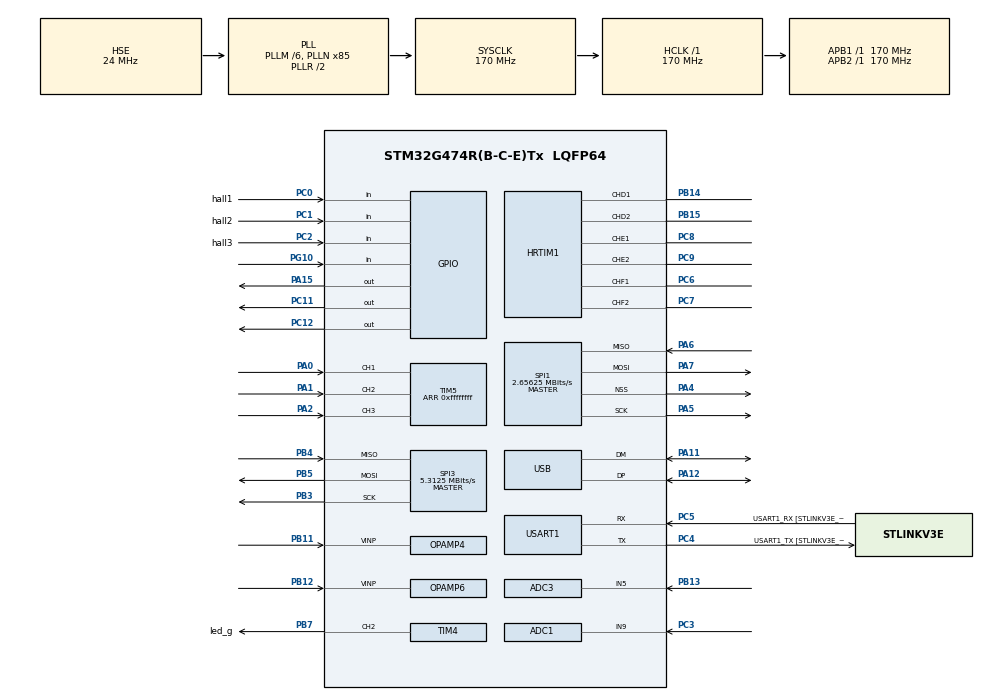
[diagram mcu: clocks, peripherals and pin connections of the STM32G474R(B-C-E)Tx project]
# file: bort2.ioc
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ADC1.Channel-10\#ChannelRegularConversion=ADC_CHANNEL_9
ADC1.ClockPrescaler=ADC_CLOCK_SYNC_PCLK_DIV4
ADC1.EOCSelection=ADC_EOC_SEQ_CONV
ADC1.EnableInjectedConversion=ENABLE
ADC1.EnableRegularConversion=ENABLE
ADC1.ExternalTrigConv=ADC_EXTERNALTRIG_HRTIM_TRG5
ADC1.ExternalTrigInjecConv=ADC_EXTERNALTRIGINJEC_HRTIM_TRG5
ADC1.InjNumberOfConversion=2
ADC1.InjectedChannel-7\#ChannelInjectedConversion=ADC_CHANNEL_11
ADC1.InjectedChannel-9\#ChannelInjectedConversion=ADC_CHANNEL_11
ADC1.InjectedOffsetNumber-7\#ChannelInjectedConversion=ADC_OFFSET_NONE
ADC1.InjectedOffsetNumber-9\#ChannelInjectedConversion=ADC_OFFSET_NONE
ADC1.InjectedRank-7\#ChannelInjectedConversion=1
ADC1.InjectedRank-9\#ChannelInjectedConversion=2
ADC1.InjectedSamplingTime-7\#ChannelInjectedConversion=ADC_SAMPLETIME_12CYCLES_5
ADC1.InjectedSamplingTime-9\#ChannelInjectedConversion=ADC_SAMPLETIME_6CYCLES_5
ADC1.NbrOfConversion=1
ADC1.NbrOfConversionFlag=1
ADC1.OffsetNumber-10\#ChannelRegularConversion=ADC_OFFSET_NONE
ADC1.Overrun=ADC_OVR_DATA_OVERWRITTEN
ADC1.Rank-10\#ChannelRegularConversion=1
ADC1.SamplingTime-10\#ChannelRegularConversion=ADC_SAMPLETIME_92CYCLES_5
ADC1.master=1
ADC2.ClockPrescaler=ADC_CLOCK_SYNC_PCLK_DIV4
ADC2.EnableInjectedConversion=ENABLE
ADC2.EnableRegularConversion=DISABLE
ADC2.ExternalTrigInjecConv=ADC_EXTERNALTRIGINJEC_HRTIM_TRG5
ADC2.InjNumberOfConversion=1
ADC2.InjectedChannel-7\#ChannelInjectedConversion=ADC_CHANNEL_14
ADC2.InjectedOffsetNumber-7\#ChannelInjectedConversion=ADC_OFFSET_NONE
ADC2.InjectedRank-7\#ChannelInjectedConversion=1
ADC2.InjectedSamplingTime-7\#ChannelInjectedConversion=ADC_SAMPLETIME_2CYCLES_5
ADC2.Overrun=ADC_OVR_DATA_OVERWRITTEN
ADC2.Rank1_Channel=ADC_CHANNEL_14
ADC3.ClockPrescaler=ADC_CLOCK_SYNC_PCLK_DIV4
ADC3.EOCSelection=ADC_EOC_SEQ_CONV
ADC3.EnableInjectedConversion=ENABLE
ADC3.EnableInjectedOversampling=DISABLE
ADC3.EnableRegularConversion=DISABLE
ADC3.ExternalTrigInjecConv=ADC_EXTERNALTRIGINJEC_HRTIM_TRG5
ADC3.InjNumberOfConversion=2
ADC3.InjectedChannel-5\#ChannelInjectedConversion=ADC_CHANNEL_VOPAMP3_ADC3
ADC3.InjectedChannel-6\#ChannelInjectedConversion=ADC_CHANNEL_5
ADC3.InjectedOffsetNumber-5\#ChannelInjectedConversion=ADC_OFFSET_NONE
ADC3.InjectedOffsetNumber-6\#ChannelInjectedConversion=ADC_OFFSET_NONE
ADC3.InjectedRank-5\#ChannelInjectedConversion=1
ADC3.InjectedRank-6\#ChannelInjectedConversion=2
ADC3.InjectedSamplingTime-5\#ChannelInjectedConversion=ADC_SAMPLETIME_12CYCLES_5
ADC3.InjectedSamplingTime-6\#ChannelInjectedConversion=ADC_SAMPLETIME_12CYCLES_5
ADC3.Overrun=ADC_OVR_DATA_OVERWRITTEN
ADC3.Rank1_Channel=ADC_CHANNEL_VOPAMP3_ADC3
ADC3.Rank2_Channel=ADC_CHANNEL_5
ADC3.Rank3_Channel=ADC_CHANNEL_5
ADC3.Rank4_Channel=ADC_CHANNEL_VOPAMP3_ADC3
ADC3.master=1
ADC4.ClockPrescaler=ADC_CLOCK_SYNC_PCLK_DIV4
ADC4.EnableInjectedConversion=ENABLE
ADC4.EnableRegularConversion=DISABLE
ADC4.ExternalTrigInjecConv=ADC_EXTERNALTRIGINJEC_HRTIM_TRG5
ADC4.InjNumberOfConversion=1
ADC4.InjectedChannel-3\#ChannelInjectedConversion=ADC_CHANNEL_VOPAMP6
ADC4.InjectedOffsetNumber-3\#ChannelInjectedConversion=ADC_OFFSET_NONE
ADC4.InjectedRank-3\#ChannelInjectedConversion=1
ADC4.InjectedSamplingTime-3\#ChannelInjectedConversion=ADC_SAMPLETIME_12CYCLES_5
ADC4.Overrun=ADC_OVR_DATA_OVERWRITTEN
ADC4.Rank1_Channel=ADC_CHANNEL_VOPAMP6
ADC5.ClockPrescaler=ADC_CLOCK_SYNC_PCLK_DIV4
ADC5.EnableInjectedConversion=ENABLE
ADC5.EnableRegularConversion=DISABLE
ADC5.ExternalTrigInjecConv=ADC_EXTERNALTRIGINJEC_HRTIM_TRG5
ADC5.InjNumberOfConversion=1
ADC5.InjectedChannel-5\#ChannelInjectedConversion=ADC_CHANNEL_VOPAMP4
ADC5.InjectedOffsetNumber-5\#ChannelInjectedConversion=ADC_OFFSET_NONE
ADC5.InjectedRank-5\#ChannelInjectedConversion=1
ADC5.InjectedSamplingTime-5\#ChannelInjectedConversion=ADC_SAMPLETIME_12CYCLES_5
ADC5.Overrun=ADC_OVR_DATA_OVERWRITTEN
ADC5.Rank1_Channel=ADC_CHANNEL_VOPAMP4
Dma.Request0=SPI3_TX
Dma.Request1=SPI3_RX
Dma.SPI3_RX.1.Direction=DMA_PERIPH_TO_MEMORY
Dma.SPI3_RX.1.EventEnable=DISABLE
Dma.SPI3_RX.1.Instance=DMA1_Channel2
Dma.SPI3_RX.1.MemDataAlignment=DMA_MDATAALIGN_HALFWORD
Dma.SPI3_RX.1.MemInc=DMA_MINC_ENABLE
Dma.SPI3_RX.1.Mode=DMA_NORMAL
Dma.SPI3_RX.1.PeriphDataAlignment=DMA_PDATAALIGN_HALFWORD
Dma.SPI3_RX.1.PeriphInc=DMA_PINC_DISABLE
Dma.SPI3_RX.1.Polarity=HAL_DMAMUX_REQ_GEN_RISING
Dma.SPI3_RX.1.Priority=DMA_PRIORITY_LOW
Dma.SPI3_RX.1.RequestNumber=1
Dma.SPI3_RX.1.SignalID=NONE
Dma.SPI3_RX.1.SyncEnable=DISABLE
Dma.SPI3_RX.1.SyncPolarity=HAL_DMAMUX_SYNC_NO_EVENT
Dma.SPI3_RX.1.SyncRequestNumber=1
Dma.SPI3_RX.1.SyncSignalID=NONE
Dma.SPI3_TX.0.Direction=DMA_MEMORY_TO_PERIPH
Dma.SPI3_TX.0.EventEnable=DISABLE
Dma.SPI3_TX.0.Instance=DMA1_Channel1
Dma.SPI3_TX.0.MemDataAlignment=DMA_MDATAALIGN_HALFWORD
Dma.SPI3_TX.0.MemInc=DMA_MINC_ENABLE
Dma.SPI3_TX.0.Mode=DMA_NORMAL
Dma.SPI3_TX.0.PeriphDataAlignment=DMA_PDATAALIGN_HALFWORD
Dma.SPI3_TX.0.PeriphInc=DMA_PINC_DISABLE
Dma.SPI3_TX.0.Polarity=HAL_DMAMUX_REQ_GEN_RISING
Dma.SPI3_TX.0.Priority=DMA_PRIORITY_LOW
Dma.SPI3_TX.0.RequestNumber=1
Dma.SPI3_TX.0.SignalID=NONE
Dma.SPI3_TX.0.SyncEnable=DISABLE
Dma.SPI3_TX.0.SyncPolarity=HAL_DMAMUX_SYNC_NO_EVENT
Dma.SPI3_TX.0.SyncRequestNumber=1
Dma.SPI3_TX.0.SyncSignalID=NONE
HRTIM1.ADCTrigger1_Source1=HRTIM_ADCTRIGGEREVENT13_TIMERF_RESET
HRTIM1.ADCTrigger2_Source1=HRTIM_ADCTRIGGEREVENT24_TIMERF_PERIOD
HRTIM1.ADCTrigger_Id1=HRTIM_ADCTRIGGER_1
HRTIM1.ADCTrigger_Id2=__NULL
HRTIM1.ADCTrigger_Id3=__NULL
HRTIM1.ADCTrigger_Id5=HRTIM_ADCTRIGGER_5
HRTIM1.ADCTrigger_Id6=__NULL
HRTIM1.ADCTrigger_Id7=__NULL
HRTIM1.Adrom_TF=HRTIM_TIM_ADROM_VALLEY
HRTIM1.Configuration_TD=Simple
HRTIM1.Configuration_TE=Simple
HRTIM1.Configuration_TF=Simple
HRTIM1.EnableCalibration=DLLSimpleCalibration
HRTIM1.NumberADCTriggerSource1=1
HRTIM1.NumberADCTriggerSource2=1
HRTIM1.OCChannel_TD1=HRTIM_OUTPUT_TD1
HRTIM1.OCChannel_TE1=HRTIM_OUTPUT_TE1
HRTIM1.OCChannel_TF1=HRTIM_OUTPUT_TF1
HRTIM1.OCChannel_TF2=__NULL
HRTIM1.OCMode_TD1=HRTIM_BASICOCMODE_ACTIVE
HRTIM1.OCMode_TE1=HRTIM_BASICOCMODE_ACTIVE
HRTIM1.OCMode_TF1=HRTIM_BASICOCMODE_ACTIVE
HRTIM1.OCMode_TF2=HRTIM_BASICOCMODE_INACTIVE
HRTIM1.OCPolarity_TD1=HRTIM_OUTPUTPOLARITY_HIGH
HRTIM1.OCPolarity_TE1=HRTIM_OUTPUTPOLARITY_HIGH
HRTIM1.OCPolarity_TF1=HRTIM_OUTPUTPOLARITY_HIGH
HRTIM1.OCPulse_TD1=hrperiod/2
HRTIM1.OCPulse_TE1=hrperiod/2
HRTIM1.OCPulse_TF1=hrperiod/2
HRTIM1.OCPulse_TF2=4000
HRTIM1.ORingUpdateSource_ADCTrigger1=HRTIM_ADCTRIGGERUPDATE_TIMER_F
HRTIM1.ORingUpdateSource_ADCTrigger5=HRTIM_ADCTRIGGERUPDATE_TIMER_F
HRTIM1.PWMChannel_TF1=__NULL
HRTIM1.PWMChannel_TF2=__NULL
HRTIM1.Periode_TD=hrperiod
HRTIM1.Periode_TE=hrperiod
HRTIM1.Periode_TF=hrperiod
HRTIM1.PrescalerRatio_TF=HRTIM_PRESCALERRATIO_MUL32
HRTIM1.Source_ADCTrigger5=HRTIM_ADCTRIGGEREVENT579_TIMERF_PERIOD
HRTIM1.UpDownMode-Output_TD1TD2=HRTIM_TIMERUPDOWNMODE_UPDOWN
HRTIM1.UpDownMode-Output_TE1TE2=HRTIM_TIMERUPDOWNMODE_UPDOWN
HRTIM1.UpDownMode-Output_TF1TF2=HRTIM_TIMERUPDOWNMODE_UPDOWN
HRTIM1.postscaler5=0
Mcu.Family=STM32G4
Mcu.Name=STM32G474R(B-C-E)Tx
Mcu.Package=LQFP64
Mcu.UserConstants=hrperiod,27200*2;main_loop_period,170e6/10000
NVIC.ADC1_2_IRQn=true\:0\:0\:false\:false\:true\:true\:true
NVIC.DMA1_Channel1_IRQn=true\:0\:0\:false\:false\:true\:false\:true
NVIC.DMA1_Channel2_IRQn=true\:0\:0\:false\:false\:true\:false\:true
NVIC.HRTIM1_Master_IRQn=true\:0\:0\:false\:false\:true\:false\:true
NVIC.PriorityGroup=NVIC_PRIORITYGROUP_4
NVIC.TIM1_UP_TIM16_IRQn=true\:0\:0\:false\:false\:true\:true\:true
NVIC.USB_HP_IRQn=true\:0\:0\:false\:false\:true\:true\:true
NVIC.USB_LP_IRQn=true\:0\:0\:false\:false\:true\:true\:true
OPAMP3.PowerMode=OPAMP_POWERMODE_HIGHSPEED
OPAMP4.PowerMode=OPAMP_POWERMODE_HIGHSPEED
OPAMP6.PowerMode=OPAMP_POWERMODE_HIGHSPEED
PA0.Signal=S_TIM5_CH1
PA1.Signal=S_TIM5_CH2
PA11.Mode=Device
PA11.Signal=USB_DM
PA12.Mode=Device
PA12.Signal=USB_DP
PA13.GPIO_Label=T_SWDIO
PA13.Signal=SYS_JTMS-SWDIO
PA14.GPIO_Label=T_SWCLK
PA14.Signal=SYS_JTCK-SWCLK
PA15.GPIO_Speed=GPIO_SPEED_FREQ_VERY_HIGH
PA15.PinState=GPIO_PIN_SET
PA15.Signal=GPIO_Output
PA2.Signal=S_TIM5_CH3
PA4.Mode=NSS_Signal_Hard_Output
PA4.Signal=SPI1_NSS
PA5.Mode=Full_Duplex_Master
PA5.Signal=SPI1_SCK
PA6.Mode=Full_Duplex_Master
PA6.Signal=SPI1_MISO
PA7.Mode=Full_Duplex_Master
PA7.Signal=SPI1_MOSI
PB11.Signal=SharedAnalog_PB11
PB12.Signal=SharedAnalog_PB12
PB13.Signal=SharedAnalog_PB13
PB14.Mode=Output_TD1TD2
PB14.Signal=HRTIM1_CHD1
PB15.Mode=Output_TD1TD2
PB15.Signal=HRTIM1_CHD2
PB3.GPIO_Speed=GPIO_SPEED_FREQ_VERY_HIGH
PB3.Mode=Full_Duplex_Master
PB3.Signal=SPI3_SCK
PB4.GPIO_Speed=GPIO_SPEED_FREQ_VERY_HIGH
PB4.Mode=Full_Duplex_Master
PB4.Signal=SPI3_MISO
PB5.GPIO_Speed=GPIO_SPEED_FREQ_VERY_HIGH
PB5.Mode=Full_Duplex_Master
PB5.Signal=SPI3_MOSI
PB7.GPIO_Label=led_g
PB7.GPIO_Speed=GPIO_SPEED_FREQ_VERY_HIGH
PB7.Signal=S_TIM4_CH2
PC0.GPIO_Label=hall1
PC0.Signal=GPIO_Input
PC1.GPIO_Label=hall2
PC1.Signal=GPIO_Input
PC11.Signal=GPIO_Output
PC12.GPIO_Speed=GPIO_SPEED_FREQ_VERY_HIGH
PC12.PinState=GPIO_PIN_SET
PC12.Signal=GPIO_Output
PC14-OSC32_IN.Mode=LSE-External-Oscillator
PC14-OSC32_IN.Signal=RCC_OSC32_IN
PC15-OSC32_OUT.Mode=LSE-External-Oscillator
PC15-OSC32_OUT.Signal=RCC_OSC32_OUT
PC2.GPIO_Label=hall3
PC2.Signal=GPIO_Input
PC3.Mode=IN9-Single-Ended
PC3.Signal=ADC1_IN9
PC4.GPIO_Label=USART1_TX [STLINKV3E_VCP_RX]
PC4.Mode=Asynchronous
PC4.Signal=USART1_TX
PC5.GPIO_Label=USART1_RX [STLINKV3E_VCP_TX]
PC5.Mode=Asynchronous
PC5.Signal=USART1_RX
PC6.Mode=Output_TF1TF2
PC6.Signal=HRTIM1_CHF1
PC7.Mode=Output_TF1TF2
PC7.Signal=HRTIM1_CHF2
PC8.Mode=Output_TE1TE2
PC8.Signal=HRTIM1_CHE1
PC9.Mode=Output_TE1TE2
PC9.Signal=HRTIM1_CHE2
PF0-OSC_IN.Mode=HSE-External-Oscillator
PF0-OSC_IN.Signal=RCC_OSC_IN
PF1-OSC_OUT.Mode=HSE-External-Oscillator
PF1-OSC_OUT.Signal=RCC_OSC_OUT
PG10-NRST.Signal=GPIO_Input
ProjectManager.HeapSize=0x2000
ProjectManager.StackSize=0x4000
ProjectManager.TargetToolchain=Makefile
RCC.ADC12CLockSelection=RCC_ADC12CLKSOURCE_PLL
RCC.ADC12Freq_Value=56666666.666666664
RCC.ADC345CLockSelection=RCC_ADC345CLKSOURCE_PLL
RCC.ADC345Freq_Value=56666666.666666664
RCC.AHBFreq_Value=170000000
RCC.APB1Freq_Value=170000000
RCC.APB1TimFreq_Value=170000000
RCC.APB2Freq_Value=170000000
RCC.APB2TimFreq_Value=170000000
RCC.CK48CLockSelection=RCC_USBCLKSOURCE_HSI48
RCC.CortexFreq_Value=170000000
RCC.EXTERNAL_CLOCK_VALUE=12288000
RCC.HCLKFreq_Value=170000000
RCC.HSE_VALUE=24000000
RCC.HSI48_VALUE=48000000
RCC.HSI_VALUE=16000000
RCC.PLLM=RCC_PLLM_DIV6
RCC.PLLN=85
RCC.PLLP=RCC_PLLP_DIV6
RCC.PLLQ=RCC_PLLQ_DIV8
RCC.PLLSourceVirtual=RCC_PLLSOURCE_HSE
RCC.PREFETCH_ENABLE=1
RCC.RTCClockSelection=RCC_RTCCLKSOURCE_LSE
RCC.SYSCLKFreq_VALUE=170000000
RCC.SYSCLKSource=RCC_SYSCLKSOURCE_PLLCLK
RCC.USBFreq_Value=48000000
RCC.VCOOutputFreq_Value=340000000
SH.S_TIM4_CH2.0=TIM4_CH2,PWM Generation2 CH2
SH.S_TIM5_CH1.0=TIM5_CH1,Encoder_Interface
SH.S_TIM5_CH2.0=TIM5_CH2,Encoder_Interface
SH.S_TIM5_CH3.0=TIM5_CH3,Input_Capture3_from_TI3
SH.SharedAnalog_PB11.0=OPAMP4_VINP,Follower_Internally_Connected
SH.SharedAnalog_PB11.1=ADC2_IN14,IN14-Single-Ended
SH.SharedAnalog_PB12.0=OPAMP6_VINP,Follower_Internally_Connected
SH.SharedAnalog_PB12.1=ADC1_IN11,IN11-Single-Ended
SH.SharedAnalog_PB13.0=ADC3_IN5,IN5-Single-Ended
SH.SharedAnalog_PB13.1=OPAMP3_VINP,Follower_Internally_Connected
SPI1.BaudRatePrescaler=SPI_BAUDRATEPRESCALER_64
SPI1.CalculateBaudRate=2.65625 MBits/s
SPI1.DataSize=SPI_DATASIZE_16BIT
SPI1.Direction=SPI_DIRECTION_2LINES
SPI1.Mode=SPI_MODE_MASTER
SPI1.TIMode=SPI_TIMODE_ENABLE
SPI1.VirtualNSS=VM_NSSHARD
SPI1.VirtualType=VM_MASTER
SPI3.BaudRatePrescaler=SPI_BAUDRATEPRESCALER_32
SPI3.CLKPhase=SPI_PHASE_2EDGE
SPI3.CLKPolarity=SPI_POLARITY_LOW
SPI3.CalculateBaudRate=5.3125 MBits/s
SPI3.DataSize=SPI_DATASIZE_16BIT
SPI3.Direction=SPI_DIRECTION_2LINES
SPI3.Mode=SPI_MODE_MASTER
SPI3.VirtualType=VM_MASTER
TIM1.PeriodNoDither=main_loop_period-1
TIM4.Channel-PWM\ Generation2\ CH2=TIM_CHANNEL_2
TIM4.PeriodNoDither=0xFFFF
TIM5.Channel-Input_Capture3_from_TI3=TIM_CHANNEL_3
TIM5.EncoderMode=TIM_ENCODERMODE_TI12
TIM5.IC1Filter=1
TIM5.IC2Filter=1
TIM5.ICFilter_CH3=2
TIM5.PeriodNoDither=0xffffffff
USART1.VirtualMode-Asynchronous=VM_ASYNC
USART1.WordLength=WORDLENGTH_8B
VP_ADC3_OPAMP_INTERNAL3.Mode=IN-OPAMP3
VP_ADC4_OPAMP_INTERNAL6.Mode=IN-OPAMP6
VP_ADC5_OPAMP_INTERNAL4.Mode=IN-OPAMP4
VP_RCC_VS_USB.Mode=USB_FS
VP_SYS_VS_DBSignals.Mode=DisableDeadBatterySignals
VP_TIM1_VS_ClockSourceINT.Mode=Internal
board=NUCLEO-G474RE

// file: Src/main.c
/* USER CODE BEGIN Header */
/**
  ******************************************************************************
  * @file           : main.c
  * @brief          : Main program body
  ******************************************************************************
  * @attention
  *
  * <h2><center>&copy; Copyright (c) 2019 STMicroelectronics.
  * All rights reserved.</center></h2>
  *
  * This software component is licensed by ST under Ultimate Liberty license
  * SLA0044, the "License"; You may not use this file except in compliance with
  * the License. You may obtain a copy of the License at:
  *                             www.st.com/SLA0044
  *
  ******************************************************************************
  */
/* USER CODE END Header */

#include "main.h"

/* USER CODE BEGIN Includes */
#include "../motorlib/system.h"
uint8_t go_to_bootloader = 0;
/* USER CODE END Includes */

ADC_HandleTypeDef hadc1;
ADC_HandleTypeDef hadc2;
ADC_HandleTypeDef hadc3;
ADC_HandleTypeDef hadc4;
ADC_HandleTypeDef hadc5;

HRTIM_HandleTypeDef hhrtim1;

OPAMP_HandleTypeDef hopamp3;
OPAMP_HandleTypeDef hopamp4;
OPAMP_HandleTypeDef hopamp6;

SPI_HandleTypeDef hspi1;
SPI_HandleTypeDef hspi3;
DMA_HandleTypeDef hdma_spi3_tx;
DMA_HandleTypeDef hdma_spi3_rx;

TIM_HandleTypeDef htim1;
TIM_HandleTypeDef htim4;
TIM_HandleTypeDef htim5;

UART_HandleTypeDef huart1;

PCD_HandleTypeDef hpcd_USB_FS;

/* USER CODE BEGIN PV */
#include "../motorlib/param.h"
//#include "main2.h"

/* USER CODE END PV */

void SystemClock_Config(void);
static void MX_GPIO_Init(void);
static void MX_USART1_UART_Init(void);
static void MX_HRTIM1_Init(void);
static void MX_ADC1_Init(void);
static void MX_ADC2_Init(void);
static void MX_ADC3_Init(void);
static void MX_TIM5_Init(void);
static void MX_SPI1_Init(void);
static void MX_SPI3_Init(void);
static void MX_DMA_Init(void);
static void MX_ADC4_Init(void);
static void MX_ADC5_Init(void);
static void MX_OPAMP3_Init(void);
static void MX_OPAMP4_Init(void);
static void MX_OPAMP6_Init(void);
static void MX_USB_PCD_Init(void);
static void MX_TIM1_Init(void);
static void MX_TIM4_Init(void);

/* USER CODE BEGIN 0 */
uint16_t drv_regs_error = 0;

uint16_t drv_regs[] = {
  (2<<11) | 0x00,  // control_reg 0x00, 6 PWM mode
  (3<<11) | 0x3AA, // hs_reg      0x3CC, moderate drive current
  (4<<11) | 0x2FF, // ls_reg      0x0CC, no cycle by cycle, 500 ns tdrive
                                // moderate drive current (.57,1.14A)
  (5<<11) | 0x020,  // ocp_reg     0x20 -> 50 ns dead time,
                              //latched ocp, 4 us ocp deglitch, 0.06 Vds thresh
  //(6<<11) | 0x2C0, // csa_reg     0x2C0 -> bidirectional current, 40V/V
  (6<<11) | 0x280, // csa_reg     0x280 -> bidirectional current, 20V/V
};

/* USER CODE END 0 */

int main(void)
{
  /* USER CODE BEGIN 1 */
  // DWC CYCCNT used as main counter
  CoreDebug->DEMCR |= CoreDebug_DEMCR_TRCENA_Msk;
  DWT->CYCCNT = 0;
  DWT->CTRL |= DWT_CTRL_CYCCNTENA_Msk;
  /* USER CODE END 1 */

  /* MCU Configuration--------------------------------------------------------*/

  /* Reset of all peripherals, Initializes the Flash interface and the Systick. */
  HAL_Init();

  /* USER CODE BEGIN Init */
  RCC->APB1ENR1 |= RCC_APB1ENR1_CRSEN;      // Clock recovery circuit, enables syncing HSI48 MHz to USB clock
  /* USER CODE END Init */

  /* Configure the system clock */
  SystemClock_Config();

  /* USER CODE BEGIN SysInit */
  DWT->CTRL = 0x400003FF | (1ul<<17) | DWT_CTRL_LSUEVTENA_Msk | DWT_CTRL_FOLDEVTENA_Msk;
  system_init();
  /* USER CODE END SysInit */

  /* Initialize all configured peripherals */
  MX_GPIO_Init();
  MX_USART1_UART_Init();
  MX_HRTIM1_Init();
  MX_ADC1_Init();
  MX_ADC2_Init();
  MX_ADC3_Init();
  MX_TIM5_Init();
  MX_SPI1_Init();
  MX_SPI3_Init();
  MX_DMA_Init();
  MX_ADC4_Init();
  MX_ADC5_Init();
  MX_OPAMP3_Init();
  MX_OPAMP4_Init();
  MX_OPAMP6_Init();
  MX_USB_PCD_Init();
  MX_TIM1_Init();
  MX_TIM4_Init();
  /* USER CODE BEGIN 2 */

  HAL_ADC_Start(&hadc1);
  HAL_ADC_Start(&hadc2);
  HAL_ADC_Start(&hadc3);
  HAL_ADC_Start(&hadc4);
  HAL_ADC_Start(&hadc5);

  HAL_OPAMP_Start(&hopamp3);
  HAL_OPAMP_Start(&hopamp4);
  OPAMP6->CSR |= OPAMP_CSR_OPAMPINTEN; // bug in cubemx
  HAL_OPAMP_Start(&hopamp6);
  HAL_Delay(100);

    SPI3->CR1 |= SPI_CR1_SPE;

  GPIOC->ODR |= GPIO_ODR_OD11; // drv enable
  HAL_Delay(10);

  for (uint8_t i=0; i<sizeof(drv_regs)/sizeof(uint16_t); i++) {
    uint16_t reg_out = drv_regs[i];
    uint16_t reg_in = 0;
    HAL_SPI_TransmitReceive(&hspi1, (uint8_t *) &reg_out, (uint8_t *) &reg_in, 1, 10);
     reg_out |= (1<<15); // switch to read mode
     HAL_SPI_TransmitReceive(&hspi1, (uint8_t *) &reg_out, (uint8_t *) &reg_in, 1, 10);
    if ((reg_in & 0x7FF) != (reg_out & 0x7FF)) {
      drv_regs_error |= 1 << i;
    }
  }
  uint32_t deadtime = 10;
  uint32_t deadprescale = 0;
  HRTIM1->sTimerxRegs[3].OUTxR |= HRTIM_OUTR_DTEN;
  HRTIM1->sTimerxRegs[3].DTxR |= (deadtime << HRTIM_DTR_DTF_Pos) | (deadtime << HRTIM_DTR_DTR_Pos) | (deadprescale << HRTIM_DTR_DTPRSC_Pos);
  HRTIM1->sTimerxRegs[3].TIMxCR |= HRTIM_TIMCR_PREEN | HRTIM_TIMCR_TRSTU;
  HRTIM1->sTimerxRegs[4].OUTxR |= HRTIM_OUTR_DTEN;
  HRTIM1->sTimerxRegs[4].DTxR |= (deadtime << HRTIM_DTR_DTF_Pos) | (deadtime << HRTIM_DTR_DTR_Pos) | (deadprescale << HRTIM_DTR_DTPRSC_Pos);
  HRTIM1->sTimerxRegs[4].TIMxCR |= HRTIM_TIMCR_PREEN | HRTIM_TIMCR_TRSTU;
  HRTIM1->sTimerxRegs[5].OUTxR |= HRTIM_OUTR_DTEN;
  HRTIM1->sTimerxRegs[5].DTxR |= (deadtime << HRTIM_DTR_DTF_Pos) | (deadtime << HRTIM_DTR_DTR_Pos) | (deadprescale << HRTIM_DTR_DTPRSC_Pos);
  HRTIM1->sTimerxRegs[5].TIMxCR |= HRTIM_TIMCR_PREEN | HRTIM_TIMCR_TRSTU;

  //HRTIM1->sCommonRegs.CR2 |= HRTIM_CR2_TESWU;
  HRTIM1->sMasterRegs.MCR |= HRTIM_MCR_TDCEN + HRTIM_MCR_TECEN + HRTIM_MCR_TFCEN;

  HAL_HRTIM_SimplePWMStart(&hhrtim1, HRTIM_TIMERINDEX_TIMER_D, HRTIM_OUTPUT_TD1);
  HAL_HRTIM_SimplePWMStart(&hhrtim1, HRTIM_TIMERINDEX_TIMER_D, HRTIM_OUTPUT_TD2);
  HAL_HRTIM_SimplePWMStart(&hhrtim1, HRTIM_TIMERINDEX_TIMER_E, HRTIM_OUTPUT_TE2);
  HAL_HRTIM_SimplePWMStart(&hhrtim1, HRTIM_TIMERINDEX_TIMER_E, HRTIM_OUTPUT_TF1);
  HAL_HRTIM_SimplePWMStart(&hhrtim1, HRTIM_TIMERINDEX_TIMER_F, HRTIM_OUTPUT_TE1);
  HAL_HRTIM_SimplePWMStart(&hhrtim1, HRTIM_TIMERINDEX_TIMER_F, HRTIM_OUTPUT_TF2);
  hadc1.Instance->CR |= ADC_CR_JADSTART;
  hadc1.Instance->IER |= ADC_IER_JEOCIE;
  hadc2.Instance->CR |= ADC_CR_JADSTART;
  hadc3.Instance->CR |= ADC_CR_JADSTART;
  hadc4.Instance->CR |= ADC_CR_JADSTART;
  hadc5.Instance->CR |= ADC_CR_JADSTART;

  // interrupt priorities
  HAL_NVIC_SetPriority(SysTick_IRQn, 4, 0);
  HAL_NVIC_SetPriority(USB_HP_IRQn, 2, 0);
  HAL_NVIC_SetPriority(USB_LP_IRQn, 3, 0);
  HAL_NVIC_SetPriority(TIM1_UP_TIM16_IRQn, 1, 0);

  HAL_TIM_Encoder_Start(&htim5, TIM_CHANNEL_ALL);
  USB->CNTR &= ~(USB_CNTR_SOFM | USB_CNTR_ESOFM); // Don't need these interrupts
  USB_DevConnect(USB);
  htim1.Instance->DIER |= TIM_DIER_UIE;
  HAL_TIM_Base_Start(&htim1);
  HAL_TIM_Base_Start(&htim4);
  HAL_TIM_IC_Start(&htim5, TIM_CHANNEL_3); // encoder index
  HAL_TIM_OC_Start(&htim4, TIM_CHANNEL_2);

  /* USER CODE END 2 */

  /* Infinite loop */
  /* USER CODE BEGIN WHILE */
  int i = 0;
  while (1)
  {
    i++;
    system_run();
   // USB_send(&i,sizeof(int));
    /* USER CODE END WHILE */

  }
}

void SystemClock_Config(void)
{
  RCC_OscInitTypeDef RCC_OscInitStruct = {0};
  RCC_ClkInitTypeDef RCC_ClkInitStruct = {0};
  RCC_PeriphCLKInitTypeDef PeriphClkInit = {0};
  RCC_CRSInitTypeDef pInit = {0};

  /** Configure the main internal regulator output voltage
  */
  HAL_PWREx_ControlVoltageScaling(PWR_REGULATOR_VOLTAGE_SCALE1_BOOST);
  /** Initializes the CPU, AHB and APB busses clocks
  */
  RCC_OscInitStruct.OscillatorType = RCC_OSCILLATORTYPE_HSI48|RCC_OSCILLATORTYPE_HSE;
  RCC_OscInitStruct.HSEState = RCC_HSE_ON;
  RCC_OscInitStruct.HSI48State = RCC_HSI48_ON;
  RCC_OscInitStruct.PLL.PLLState = RCC_PLL_ON;
  RCC_OscInitStruct.PLL.PLLSource = RCC_PLLSOURCE_HSE;
  RCC_OscInitStruct.PLL.PLLM = RCC_PLLM_DIV6;
  RCC_OscInitStruct.PLL.PLLN = 85;
  RCC_OscInitStruct.PLL.PLLP = RCC_PLLP_DIV6;
  RCC_OscInitStruct.PLL.PLLQ = RCC_PLLQ_DIV8;
  RCC_OscInitStruct.PLL.PLLR = RCC_PLLR_DIV2;
  if (HAL_RCC_OscConfig(&RCC_OscInitStruct) != HAL_OK)
  {
    Error_Handler();
  }
  /** Initializes the CPU, AHB and APB busses clocks
  */
  RCC_ClkInitStruct.ClockType = RCC_CLOCKTYPE_HCLK|RCC_CLOCKTYPE_SYSCLK
                              |RCC_CLOCKTYPE_PCLK1|RCC_CLOCKTYPE_PCLK2;
  RCC_ClkInitStruct.SYSCLKSource = RCC_SYSCLKSOURCE_PLLCLK;
  RCC_ClkInitStruct.AHBCLKDivider = RCC_SYSCLK_DIV1;
  RCC_ClkInitStruct.APB1CLKDivider = RCC_HCLK_DIV1;
  RCC_ClkInitStruct.APB2CLKDivider = RCC_HCLK_DIV1;

  if (HAL_RCC_ClockConfig(&RCC_ClkInitStruct, FLASH_LATENCY_8) != HAL_OK)
  {
    Error_Handler();
  }
  /** Initializes the peripherals clocks
  */
  PeriphClkInit.PeriphClockSelection = RCC_PERIPHCLK_USART1|RCC_PERIPHCLK_USB
                              |RCC_PERIPHCLK_ADC12|RCC_PERIPHCLK_ADC345;
  PeriphClkInit.Usart1ClockSelection = RCC_USART1CLKSOURCE_PCLK2;
  PeriphClkInit.UsbClockSelection = RCC_USBCLKSOURCE_HSI48;
  PeriphClkInit.Adc12ClockSelection = RCC_ADC12CLKSOURCE_PLL;
  PeriphClkInit.Adc345ClockSelection = RCC_ADC345CLKSOURCE_PLL;
  if (HAL_RCCEx_PeriphCLKConfig(&PeriphClkInit) != HAL_OK)
  {
    Error_Handler();
  }
  /** Configures CRS
  */
  pInit.Prescaler = RCC_CRS_SYNC_DIV1;
  pInit.Source = RCC_CRS_SYNC_SOURCE_USB;
  pInit.Polarity = RCC_CRS_SYNC_POLARITY_RISING;
  pInit.ReloadValue = __HAL_RCC_CRS_RELOADVALUE_CALCULATE(48000000,1000);
  pInit.ErrorLimitValue = 34;
  pInit.HSI48CalibrationValue = 32;

  HAL_RCCEx_CRSConfig(&pInit);
}

static void MX_ADC1_Init(void)
{

  ADC_MultiModeTypeDef multimode = {0};
  ADC_InjectionConfTypeDef sConfigInjected = {0};
  ADC_ChannelConfTypeDef sConfig = {0};

  /** Common config
  */
  hadc1.Instance = ADC1;
  hadc1.Init.ClockPrescaler = ADC_CLOCK_SYNC_PCLK_DIV4;
  hadc1.Init.Resolution = ADC_RESOLUTION_12B;
  hadc1.Init.DataAlign = ADC_DATAALIGN_RIGHT;
  hadc1.Init.GainCompensation = 0;
  hadc1.Init.ScanConvMode = ADC_SCAN_ENABLE;
  hadc1.Init.EOCSelection = ADC_EOC_SEQ_CONV;
  hadc1.Init.LowPowerAutoWait = DISABLE;
  hadc1.Init.ContinuousConvMode = DISABLE;
  hadc1.Init.NbrOfConversion = 1;
  hadc1.Init.DiscontinuousConvMode = DISABLE;
  hadc1.Init.ExternalTrigConv = ADC_EXTERNALTRIG_HRTIM_TRG5;
  hadc1.Init.ExternalTrigConvEdge = ADC_EXTERNALTRIGCONVEDGE_RISING;
  hadc1.Init.DMAContinuousRequests = DISABLE;
  hadc1.Init.Overrun = ADC_OVR_DATA_OVERWRITTEN;
  hadc1.Init.OversamplingMode = DISABLE;
  if (HAL_ADC_Init(&hadc1) != HAL_OK)
  {
    Error_Handler();
  }
  /** Configure the ADC multi-mode
  */
  multimode.Mode = ADC_MODE_INDEPENDENT;
  if (HAL_ADCEx_MultiModeConfigChannel(&hadc1, &multimode) != HAL_OK)
  {
    Error_Handler();
  }
  /** Configure Injected Channel
  */
  sConfigInjected.InjectedChannel = ADC_CHANNEL_11;
  sConfigInjected.InjectedRank = ADC_INJECTED_RANK_1;
  sConfigInjected.InjectedSamplingTime = ADC_SAMPLETIME_12CYCLES_5;
  sConfigInjected.InjectedSingleDiff = ADC_SINGLE_ENDED;
  sConfigInjected.InjectedOffsetNumber = ADC_OFFSET_NONE;
  sConfigInjected.InjectedOffset = 0;
  sConfigInjected.InjectedNbrOfConversion = 2;
  sConfigInjected.InjectedDiscontinuousConvMode = DISABLE;
  sConfigInjected.AutoInjectedConv = DISABLE;
  sConfigInjected.QueueInjectedContext = DISABLE;
  sConfigInjected.ExternalTrigInjecConv = ADC_EXTERNALTRIGINJEC_HRTIM_TRG5;
  sConfigInjected.ExternalTrigInjecConvEdge = ADC_EXTERNALTRIGINJECCONV_EDGE_RISING;
  sConfigInjected.InjecOversamplingMode = DISABLE;
  if (HAL_ADCEx_InjectedConfigChannel(&hadc1, &sConfigInjected) != HAL_OK)
  {
    Error_Handler();
  }
  /** Configure Injected Channel
  */
  sConfigInjected.InjectedRank = ADC_INJECTED_RANK_2;
  sConfigInjected.InjectedSamplingTime = ADC_SAMPLETIME_6CYCLES_5;
  if (HAL_ADCEx_InjectedConfigChannel(&hadc1, &sConfigInjected) != HAL_OK)
  {
    Error_Handler();
  }
  /** Configure Regular Channel
  */
  sConfig.Channel = ADC_CHANNEL_9;
  sConfig.Rank = ADC_REGULAR_RANK_1;
  sConfig.SamplingTime = ADC_SAMPLETIME_92CYCLES_5;
  sConfig.SingleDiff = ADC_SINGLE_ENDED;
  sConfig.OffsetNumber = ADC_OFFSET_NONE;
  sConfig.Offset = 0;
  if (HAL_ADC_ConfigChannel(&hadc1, &sConfig) != HAL_OK)
  {
    Error_Handler();
  }

}

static void MX_ADC2_Init(void)
{

  ADC_InjectionConfTypeDef sConfigInjected = {0};

  /** Common config
  */
  hadc2.Instance = ADC2;
  hadc2.Init.ClockPrescaler = ADC_CLOCK_SYNC_PCLK_DIV4;
  hadc2.Init.Resolution = ADC_RESOLUTION_12B;
  hadc2.Init.DataAlign = ADC_DATAALIGN_RIGHT;
  hadc2.Init.GainCompensation = 0;
  hadc2.Init.ScanConvMode = ADC_SCAN_DISABLE;
  hadc2.Init.EOCSelection = ADC_EOC_SINGLE_CONV;
  hadc2.Init.LowPowerAutoWait = DISABLE;
  hadc2.Init.ContinuousConvMode = DISABLE;
  hadc2.Init.NbrOfConversion = 1;
  hadc2.Init.DiscontinuousConvMode = DISABLE;
  hadc2.Init.DMAContinuousRequests = DISABLE;
  hadc2.Init.Overrun = ADC_OVR_DATA_OVERWRITTEN;
  hadc2.Init.OversamplingMode = DISABLE;
  if (HAL_ADC_Init(&hadc2) != HAL_OK)
  {
    Error_Handler();
  }
  /** Configure Injected Channel
  */
  sConfigInjected.InjectedChannel = ADC_CHANNEL_14;
  sConfigInjected.InjectedRank = ADC_INJECTED_RANK_1;
  sConfigInjected.InjectedSamplingTime = ADC_SAMPLETIME_2CYCLES_5;
  sConfigInjected.InjectedSingleDiff = ADC_SINGLE_ENDED;
  sConfigInjected.InjectedOffsetNumber = ADC_OFFSET_NONE;
  sConfigInjected.InjectedOffset = 0;
  sConfigInjected.InjectedNbrOfConversion = 1;
  sConfigInjected.InjectedDiscontinuousConvMode = DISABLE;
  sConfigInjected.AutoInjectedConv = DISABLE;
  sConfigInjected.QueueInjectedContext = DISABLE;
  sConfigInjected.ExternalTrigInjecConv = ADC_EXTERNALTRIGINJEC_HRTIM_TRG5;
  sConfigInjected.ExternalTrigInjecConvEdge = ADC_EXTERNALTRIGINJECCONV_EDGE_RISING;
  sConfigInjected.InjecOversamplingMode = DISABLE;
  if (HAL_ADCEx_InjectedConfigChannel(&hadc2, &sConfigInjected) != HAL_OK)
  {
    Error_Handler();
  }

}

static void MX_ADC3_Init(void)
{

  ADC_MultiModeTypeDef multimode = {0};
  ADC_InjectionConfTypeDef sConfigInjected = {0};

  /** Common config
  */
  hadc3.Instance = ADC3;
  hadc3.Init.ClockPrescaler = ADC_CLOCK_SYNC_PCLK_DIV4;
  hadc3.Init.Resolution = ADC_RESOLUTION_12B;
  hadc3.Init.DataAlign = ADC_DATAALIGN_RIGHT;
  hadc3.Init.GainCompensation = 0;
  hadc3.Init.ScanConvMode = ADC_SCAN_ENABLE;
  hadc3.Init.EOCSelection = ADC_EOC_SEQ_CONV;
  hadc3.Init.LowPowerAutoWait = DISABLE;
  hadc3.Init.ContinuousConvMode = DISABLE;
  hadc3.Init.NbrOfConversion = 1;
  hadc3.Init.DiscontinuousConvMode = DISABLE;
  hadc3.Init.DMAContinuousRequests = DISABLE;
  hadc3.Init.Overrun = ADC_OVR_DATA_OVERWRITTEN;
  hadc3.Init.OversamplingMode = DISABLE;
  if (HAL_ADC_Init(&hadc3) != HAL_OK)
  {
    Error_Handler();
  }
  /** Configure the ADC multi-mode
  */
  multimode.Mode = ADC_MODE_INDEPENDENT;
  if (HAL_ADCEx_MultiModeConfigChannel(&hadc3, &multimode) != HAL_OK)
  {
    Error_Handler();
  }
  /** Configure Injected Channel
  */
  sConfigInjected.InjectedChannel = ADC_CHANNEL_VOPAMP3_ADC3;
  sConfigInjected.InjectedRank = ADC_INJECTED_RANK_1;
  sConfigInjected.InjectedSamplingTime = ADC_SAMPLETIME_12CYCLES_5;
  sConfigInjected.InjectedSingleDiff = ADC_SINGLE_ENDED;
  sConfigInjected.InjectedOffsetNumber = ADC_OFFSET_NONE;
  sConfigInjected.InjectedOffset = 0;
  sConfigInjected.InjectedNbrOfConversion = 2;
  sConfigInjected.InjectedDiscontinuousConvMode = DISABLE;
  sConfigInjected.AutoInjectedConv = DISABLE;
  sConfigInjected.QueueInjectedContext = DISABLE;
  sConfigInjected.ExternalTrigInjecConv = ADC_EXTERNALTRIGINJEC_HRTIM_TRG5;
  sConfigInjected.ExternalTrigInjecConvEdge = ADC_EXTERNALTRIGINJECCONV_EDGE_RISING;
  sConfigInjected.InjecOversamplingMode = DISABLE;
  if (HAL_ADCEx_InjectedConfigChannel(&hadc3, &sConfigInjected) != HAL_OK)
  {
    Error_Handler();
  }
  /** Configure Injected Channel
  */
  sConfigInjected.InjectedChannel = ADC_CHANNEL_5;
  sConfigInjected.InjectedRank = ADC_INJECTED_RANK_2;
  if (HAL_ADCEx_InjectedConfigChannel(&hadc3, &sConfigInjected) != HAL_OK)
  {
    Error_Handler();
  }

}

static void MX_ADC4_Init(void)
{

  ADC_InjectionConfTypeDef sConfigInjected = {0};

  /** Common config
  */
  hadc4.Instance = ADC4;
  hadc4.Init.ClockPrescaler = ADC_CLOCK_SYNC_PCLK_DIV4;
  hadc4.Init.Resolution = ADC_RESOLUTION_12B;
  hadc4.Init.DataAlign = ADC_DATAALIGN_RIGHT;
  hadc4.Init.GainCompensation = 0;
  hadc4.Init.ScanConvMode = ADC_SCAN_DISABLE;
  hadc4.Init.EOCSelection = ADC_EOC_SINGLE_CONV;
  hadc4.Init.LowPowerAutoWait = DISABLE;
  hadc4.Init.ContinuousConvMode = DISABLE;
  hadc4.Init.NbrOfConversion = 1;
  hadc4.Init.DiscontinuousConvMode = DISABLE;
  hadc4.Init.DMAContinuousRequests = DISABLE;
  hadc4.Init.Overrun = ADC_OVR_DATA_OVERWRITTEN;
  hadc4.Init.OversamplingMode = DISABLE;
  if (HAL_ADC_Init(&hadc4) != HAL_OK)
  {
    Error_Handler();
  }
  /** Configure Injected Channel
  */
  sConfigInjected.InjectedChannel = ADC_CHANNEL_VOPAMP6;
  sConfigInjected.InjectedRank = ADC_INJECTED_RANK_1;
  sConfigInjected.InjectedSamplingTime = ADC_SAMPLETIME_12CYCLES_5;
  sConfigInjected.InjectedSingleDiff = ADC_SINGLE_ENDED;
  sConfigInjected.InjectedOffsetNumber = ADC_OFFSET_NONE;
  sConfigInjected.InjectedOffset = 0;
  sConfigInjected.InjectedNbrOfConversion = 1;
  sConfigInjected.InjectedDiscontinuousConvMode = DISABLE;
  sConfigInjected.AutoInjectedConv = DISABLE;
  sConfigInjected.QueueInjectedContext = DISABLE;
  sConfigInjected.ExternalTrigInjecConv = ADC_EXTERNALTRIGINJEC_HRTIM_TRG5;
  sConfigInjected.ExternalTrigInjecConvEdge = ADC_EXTERNALTRIGINJECCONV_EDGE_RISING;
  sConfigInjected.InjecOversamplingMode = DISABLE;
  if (HAL_ADCEx_InjectedConfigChannel(&hadc4, &sConfigInjected) != HAL_OK)
  {
    Error_Handler();
  }

}

static void MX_ADC5_Init(void)
{

  ADC_InjectionConfTypeDef sConfigInjected = {0};

  /** Common config
  */
  hadc5.Instance = ADC5;
  hadc5.Init.ClockPrescaler = ADC_CLOCK_SYNC_PCLK_DIV4;
  hadc5.Init.Resolution = ADC_RESOLUTION_12B;
  hadc5.Init.DataAlign = ADC_DATAALIGN_RIGHT;
  hadc5.Init.GainCompensation = 0;
  hadc5.Init.ScanConvMode = ADC_SCAN_DISABLE;
  hadc5.Init.EOCSelection = ADC_EOC_SINGLE_CONV;
  hadc5.Init.LowPowerAutoWait = DISABLE;
  hadc5.Init.ContinuousConvMode = DISABLE;
  hadc5.Init.NbrOfConversion = 1;
  hadc5.Init.DiscontinuousConvMode = DISABLE;
  hadc5.Init.DMAContinuousRequests = DISABLE;
  hadc5.Init.Overrun = ADC_OVR_DATA_OVERWRITTEN;
  hadc5.Init.OversamplingMode = DISABLE;
  if (HAL_ADC_Init(&hadc5) != HAL_OK)
  {
    Error_Handler();
  }
  /** Configure Injected Channel
  */
  sConfigInjected.InjectedChannel = ADC_CHANNEL_VOPAMP4;
  sConfigInjected.InjectedRank = ADC_INJECTED_RANK_1;
  sConfigInjected.InjectedSamplingTime = ADC_SAMPLETIME_12CYCLES_5;
  sConfigInjected.InjectedSingleDiff = ADC_SINGLE_ENDED;
  sConfigInjected.InjectedOffsetNumber = ADC_OFFSET_NONE;
  sConfigInjected.InjectedOffset = 0;
  sConfigInjected.InjectedNbrOfConversion = 1;
  sConfigInjected.InjectedDiscontinuousConvMode = DISABLE;
  sConfigInjected.AutoInjectedConv = DISABLE;
  sConfigInjected.QueueInjectedContext = DISABLE;
  sConfigInjected.ExternalTrigInjecConv = ADC_EXTERNALTRIGINJEC_HRTIM_TRG5;
  sConfigInjected.ExternalTrigInjecConvEdge = ADC_EXTERNALTRIGINJECCONV_EDGE_RISING;
  sConfigInjected.InjecOversamplingMode = DISABLE;
  if (HAL_ADCEx_InjectedConfigChannel(&hadc5, &sConfigInjected) != HAL_OK)
  {
    Error_Handler();
  }

}

static void MX_HRTIM1_Init(void)
{

  HRTIM_ADCTriggerCfgTypeDef pADCTriggerCfg = {0};
  HRTIM_TimeBaseCfgTypeDef pTimeBaseCfg = {0};
  HRTIM_TimerCtlTypeDef pTimerCtl = {0};
  HRTIM_SimpleOCChannelCfgTypeDef pSimpleOCChannelCfg = {0};

  hhrtim1.Instance = HRTIM1;
  hhrtim1.Init.HRTIMInterruptResquests = HRTIM_IT_NONE;
  hhrtim1.Init.SyncOptions = HRTIM_SYNCOPTION_NONE;
  if (HAL_HRTIM_Init(&hhrtim1) != HAL_OK)
  {
    Error_Handler();
  }
  if (HAL_HRTIM_DLLCalibrationStart(&hhrtim1, HRTIM_CALIBRATIONRATE_3) != HAL_OK)
  {
    Error_Handler();
  }
  if (HAL_HRTIM_PollForDLLCalibration(&hhrtim1, 10) != HAL_OK)
  {
    Error_Handler();
  }
  pADCTriggerCfg.UpdateSource = HRTIM_ADCTRIGGERUPDATE_TIMER_F;
  pADCTriggerCfg.Trigger = HRTIM_ADCTRIGGEREVENT13_TIMERF_RESET;
  if (HAL_HRTIM_ADCTriggerConfig(&hhrtim1, HRTIM_ADCTRIGGER_1, &pADCTriggerCfg) != HAL_OK)
  {
    Error_Handler();
  }
  if (HAL_HRTIM_ADCPostScalerConfig(&hhrtim1, HRTIM_ADCTRIGGER_1, 0x0) != HAL_OK)
  {
    Error_Handler();
  }
  pADCTriggerCfg.Trigger = HRTIM_ADCTRIGGEREVENT579_TIMERF_PERIOD;
  if (HAL_HRTIM_ADCTriggerConfig(&hhrtim1, HRTIM_ADCTRIGGER_5, &pADCTriggerCfg) != HAL_OK)
  {
    Error_Handler();
  }
  if (HAL_HRTIM_ADCPostScalerConfig(&hhrtim1, HRTIM_ADCTRIGGER_5, 0) != HAL_OK)
  {
    Error_Handler();
  }
  pTimeBaseCfg.Period = hrperiod;
  pTimeBaseCfg.RepetitionCounter = 0x00;
  pTimeBaseCfg.PrescalerRatio = HRTIM_PRESCALERRATIO_MUL32;
  pTimeBaseCfg.Mode = HRTIM_MODE_CONTINUOUS;
  if (HAL_HRTIM_TimeBaseConfig(&hhrtim1, HRTIM_TIMERINDEX_TIMER_D, &pTimeBaseCfg) != HAL_OK)
  {
    Error_Handler();
  }
  pTimerCtl.UpDownMode = HRTIM_TIMERUPDOWNMODE_UPDOWN;
  pTimerCtl.DualChannelDacEnable = HRTIM_TIMER_DCDE_DISABLED;

  if (HAL_HRTIM_WaveformTimerControl(&hhrtim1, HRTIM_TIMERINDEX_TIMER_D, &pTimerCtl) != HAL_OK)
  {
    Error_Handler();
  }
  if (HAL_HRTIM_RollOverModeConfig(&hhrtim1, HRTIM_TIMERINDEX_TIMER_D, HRTIM_TIM_FEROM_BOTH|HRTIM_TIM_BMROM_BOTH
                              |HRTIM_TIM_ADROM_BOTH|HRTIM_TIM_OUTROM_BOTH
                              |HRTIM_TIM_ROM_BOTH) != HAL_OK)
  {
    Error_Handler();
  }
  pSimpleOCChannelCfg.Mode = HRTIM_BASICOCMODE_ACTIVE;
  pSimpleOCChannelCfg.Pulse = hrperiod/2;
  pSimpleOCChannelCfg.Polarity = HRTIM_OUTPUTPOLARITY_HIGH;
  pSimpleOCChannelCfg.IdleLevel = HRTIM_OUTPUTIDLELEVEL_INACTIVE;
  if (HAL_HRTIM_SimpleOCChannelConfig(&hhrtim1, HRTIM_TIMERINDEX_TIMER_D, HRTIM_OUTPUT_TD1, &pSimpleOCChannelCfg) != HAL_OK)
  {
    Error_Handler();
  }
  if (HAL_HRTIM_TimeBaseConfig(&hhrtim1, HRTIM_TIMERINDEX_TIMER_E, &pTimeBaseCfg) != HAL_OK)
  {
    Error_Handler();
  }
  pTimerCtl.DualChannelDacEnable = HRTIM_TIMER_DCDE_DISABLED;

  if (HAL_HRTIM_WaveformTimerControl(&hhrtim1, HRTIM_TIMERINDEX_TIMER_E, &pTimerCtl) != HAL_OK)
  {
    Error_Handler();
  }
  if (HAL_HRTIM_RollOverModeConfig(&hhrtim1, HRTIM_TIMERINDEX_TIMER_E, HRTIM_TIM_FEROM_BOTH|HRTIM_TIM_BMROM_BOTH
                              |HRTIM_TIM_ADROM_BOTH|HRTIM_TIM_OUTROM_BOTH
                              |HRTIM_TIM_ROM_BOTH) != HAL_OK)
  {
    Error_Handler();
  }
  if (HAL_HRTIM_SimpleOCChannelConfig(&hhrtim1, HRTIM_TIMERINDEX_TIMER_E, HRTIM_OUTPUT_TE1, &pSimpleOCChannelCfg) != HAL_OK)
  {
    Error_Handler();
  }
  if (HAL_HRTIM_TimeBaseConfig(&hhrtim1, HRTIM_TIMERINDEX_TIMER_F, &pTimeBaseCfg) != HAL_OK)
  {
    Error_Handler();
  }
  pTimerCtl.DualChannelDacEnable = HRTIM_TIMER_DCDE_DISABLED;

  if (HAL_HRTIM_WaveformTimerControl(&hhrtim1, HRTIM_TIMERINDEX_TIMER_F, &pTimerCtl) != HAL_OK)
  {
    Error_Handler();
  }
  if (HAL_HRTIM_RollOverModeConfig(&hhrtim1, HRTIM_TIMERINDEX_TIMER_F, HRTIM_TIM_FEROM_BOTH|HRTIM_TIM_BMROM_BOTH
                              |HRTIM_TIM_ADROM_VALLEY|HRTIM_TIM_OUTROM_BOTH
                              |HRTIM_TIM_ROM_BOTH) != HAL_OK)
  {
    Error_Handler();
  }
  if (HAL_HRTIM_SimpleOCChannelConfig(&hhrtim1, HRTIM_TIMERINDEX_TIMER_F, HRTIM_OUTPUT_TF1, &pSimpleOCChannelCfg) != HAL_OK)
  {
    Error_Handler();
  }
  HAL_HRTIM_MspPostInit(&hhrtim1);

}

static void MX_OPAMP3_Init(void)
{

  hopamp3.Instance = OPAMP3;
  hopamp3.Init.PowerMode = OPAMP_POWERMODE_HIGHSPEED;
  hopamp3.Init.Mode = OPAMP_FOLLOWER_MODE;
  hopamp3.Init.NonInvertingInput = OPAMP_NONINVERTINGINPUT_IO1;
  hopamp3.Init.InternalOutput = ENABLE;
  hopamp3.Init.TimerControlledMuxmode = OPAMP_TIMERCONTROLLEDMUXMODE_DISABLE;
  hopamp3.Init.UserTrimming = OPAMP_TRIMMING_FACTORY;
  if (HAL_OPAMP_Init(&hopamp3) != HAL_OK)
  {
    Error_Handler();
  }

}

static void MX_OPAMP4_Init(void)
{

  hopamp4.Instance = OPAMP4;
  hopamp4.Init.PowerMode = OPAMP_POWERMODE_HIGHSPEED;
  hopamp4.Init.Mode = OPAMP_FOLLOWER_MODE;
  hopamp4.Init.NonInvertingInput = OPAMP_NONINVERTINGINPUT_IO2;
  hopamp4.Init.InternalOutput = ENABLE;
  hopamp4.Init.TimerControlledMuxmode = OPAMP_TIMERCONTROLLEDMUXMODE_DISABLE;
  hopamp4.Init.UserTrimming = OPAMP_TRIMMING_FACTORY;
  if (HAL_OPAMP_Init(&hopamp4) != HAL_OK)
  {
    Error_Handler();
  }

}

static void MX_OPAMP6_Init(void)
{

  hopamp6.Instance = OPAMP6;
  hopamp6.Init.PowerMode = OPAMP_POWERMODE_HIGHSPEED;
  hopamp6.Init.Mode = OPAMP_FOLLOWER_MODE;
  hopamp6.Init.NonInvertingInput = OPAMP_NONINVERTINGINPUT_IO0;
  hopamp6.Init.InternalOutput = DISABLE;
  hopamp6.Init.TimerControlledMuxmode = OPAMP_TIMERCONTROLLEDMUXMODE_DISABLE;
  hopamp6.Init.UserTrimming = OPAMP_TRIMMING_FACTORY;
  if (HAL_OPAMP_Init(&hopamp6) != HAL_OK)
  {
    Error_Handler();
  }

}

static void MX_SPI1_Init(void)
{

  /* SPI1 parameter configuration*/
  hspi1.Instance = SPI1;
  hspi1.Init.Mode = SPI_MODE_MASTER;
  hspi1.Init.Direction = SPI_DIRECTION_2LINES;
  hspi1.Init.DataSize = SPI_DATASIZE_16BIT;
  hspi1.Init.NSS = SPI_NSS_HARD_OUTPUT;
  hspi1.Init.BaudRatePrescaler = SPI_BAUDRATEPRESCALER_64;
  hspi1.Init.TIMode = SPI_TIMODE_ENABLE;
  hspi1.Init.CRCCalculation = SPI_CRCCALCULATION_DISABLE;
  hspi1.Init.CRCPolynomial = 7;
  hspi1.Init.CRCLength = SPI_CRC_LENGTH_DATASIZE;
  hspi1.Init.NSSPMode = SPI_NSS_PULSE_DISABLE;
  if (HAL_SPI_Init(&hspi1) != HAL_OK)
  {
    Error_Handler();
  }

}

static void MX_SPI3_Init(void)
{

  /* SPI3 parameter configuration*/
  hspi3.Instance = SPI3;
  hspi3.Init.Mode = SPI_MODE_MASTER;
  hspi3.Init.Direction = SPI_DIRECTION_2LINES;
  hspi3.Init.DataSize = SPI_DATASIZE_16BIT;
  hspi3.Init.CLKPolarity = SPI_POLARITY_LOW;
  hspi3.Init.CLKPhase = SPI_PHASE_2EDGE;
  hspi3.Init.NSS = SPI_NSS_SOFT;
  hspi3.Init.BaudRatePrescaler = SPI_BAUDRATEPRESCALER_32;
  hspi3.Init.FirstBit = SPI_FIRSTBIT_MSB;
  hspi3.Init.TIMode = SPI_TIMODE_DISABLE;
  hspi3.Init.CRCCalculation = SPI_CRCCALCULATION_DISABLE;
  hspi3.Init.CRCPolynomial = 7;
  hspi3.Init.CRCLength = SPI_CRC_LENGTH_DATASIZE;
  hspi3.Init.NSSPMode = SPI_NSS_PULSE_DISABLE;
  if (HAL_SPI_Init(&hspi3) != HAL_OK)
  {
    Error_Handler();
  }

}

static void MX_TIM1_Init(void)
{

  TIM_ClockConfigTypeDef sClockSourceConfig = {0};
  TIM_MasterConfigTypeDef sMasterConfig = {0};
  TIM_BreakDeadTimeConfigTypeDef sBreakDeadTimeConfig = {0};

  htim1.Instance = TIM1;
  htim1.Init.Prescaler = 0;
  htim1.Init.CounterMode = TIM_COUNTERMODE_UP;
  htim1.Init.Period = 16999;
  htim1.Init.ClockDivision = TIM_CLOCKDIVISION_DIV1;
  htim1.Init.RepetitionCounter = 0;
  htim1.Init.AutoReloadPreload = TIM_AUTORELOAD_PRELOAD_DISABLE;
  if (HAL_TIM_Base_Init(&htim1) != HAL_OK)
  {
    Error_Handler();
  }
  sClockSourceConfig.ClockSource = TIM_CLOCKSOURCE_INTERNAL;
  if (HAL_TIM_ConfigClockSource(&htim1, &sClockSourceConfig) != HAL_OK)
  {
    Error_Handler();
  }
  sMasterConfig.MasterOutputTrigger = TIM_TRGO_RESET;
  sMasterConfig.MasterOutputTrigger2 = TIM_TRGO2_RESET;
  sMasterConfig.MasterSlaveMode = TIM_MASTERSLAVEMODE_DISABLE;
  if (HAL_TIMEx_MasterConfigSynchronization(&htim1, &sMasterConfig) != HAL_OK)
  {
    Error_Handler();
  }
  sBreakDeadTimeConfig.BreakAFMode = TIM_BREAK_AFMODE_INPUT;
  sBreakDeadTimeConfig.Break2AFMode = TIM_BREAK_AFMODE_INPUT;
  if (HAL_TIMEx_ConfigBreakDeadTime(&htim1, &sBreakDeadTimeConfig) != HAL_OK)
  {
    Error_Handler();
  }

}

static void MX_TIM4_Init(void)
{

  TIM_MasterConfigTypeDef sMasterConfig = {0};
  TIM_OC_InitTypeDef sConfigOC = {0};

  htim4.Instance = TIM4;
  htim4.Init.Prescaler = 0;
  htim4.Init.CounterMode = TIM_COUNTERMODE_UP;
  htim4.Init.Period = 65535;
  htim4.Init.ClockDivision = TIM_CLOCKDIVISION_DIV1;
  htim4.Init.AutoReloadPreload = TIM_AUTORELOAD_PRELOAD_DISABLE;
  if (HAL_TIM_PWM_Init(&htim4) != HAL_OK)
  {
    Error_Handler();
  }
  sMasterConfig.MasterOutputTrigger = TIM_TRGO_RESET;
  sMasterConfig.MasterSlaveMode = TIM_MASTERSLAVEMODE_DISABLE;
  if (HAL_TIMEx_MasterConfigSynchronization(&htim4, &sMasterConfig) != HAL_OK)
  {
    Error_Handler();
  }
  sConfigOC.OCMode = TIM_OCMODE_PWM1;
  sConfigOC.Pulse = 0;
  sConfigOC.OCPolarity = TIM_OCPOLARITY_HIGH;
  sConfigOC.OCFastMode = TIM_OCFAST_DISABLE;
  if (HAL_TIM_PWM_ConfigChannel(&htim4, &sConfigOC, TIM_CHANNEL_2) != HAL_OK)
  {
    Error_Handler();
  }
  HAL_TIM_MspPostInit(&htim4);

}

static void MX_TIM5_Init(void)
{

  TIM_Encoder_InitTypeDef sConfig = {0};
  TIM_MasterConfigTypeDef sMasterConfig = {0};
  TIM_IC_InitTypeDef sConfigIC = {0};

  htim5.Instance = TIM5;
  htim5.Init.Prescaler = 0;
  htim5.Init.CounterMode = TIM_COUNTERMODE_UP;
  htim5.Init.Period = 0xffffffff;
  htim5.Init.ClockDivision = TIM_CLOCKDIVISION_DIV1;
  htim5.Init.AutoReloadPreload = TIM_AUTORELOAD_PRELOAD_DISABLE;
  if (HAL_TIM_IC_Init(&htim5) != HAL_OK)
  {
    Error_Handler();
  }
  sConfig.EncoderMode = TIM_ENCODERMODE_TI12;
  sConfig.IC1Polarity = TIM_ICPOLARITY_RISING;
  sConfig.IC1Selection = TIM_ICSELECTION_DIRECTTI;
  sConfig.IC1Prescaler = TIM_ICPSC_DIV1;
  sConfig.IC1Filter = 1;
  sConfig.IC2Polarity = TIM_ICPOLARITY_RISING;
  sConfig.IC2Selection = TIM_ICSELECTION_DIRECTTI;
  sConfig.IC2Prescaler = TIM_ICPSC_DIV1;
  sConfig.IC2Filter = 1;
  if (HAL_TIM_Encoder_Init(&htim5, &sConfig) != HAL_OK)
  {
    Error_Handler();
  }
  sMasterConfig.MasterOutputTrigger = TIM_TRGO_RESET;
  sMasterConfig.MasterSlaveMode = TIM_MASTERSLAVEMODE_DISABLE;
  if (HAL_TIMEx_MasterConfigSynchronization(&htim5, &sMasterConfig) != HAL_OK)
  {
    Error_Handler();
  }
  sConfigIC.ICPolarity = TIM_INPUTCHANNELPOLARITY_RISING;
  sConfigIC.ICSelection = TIM_ICSELECTION_DIRECTTI;
  sConfigIC.ICPrescaler = TIM_ICPSC_DIV1;
  sConfigIC.ICFilter = 2;
  if (HAL_TIM_IC_ConfigChannel(&htim5, &sConfigIC, TIM_CHANNEL_3) != HAL_OK)
  {
    Error_Handler();
  }

}

static void MX_USART1_UART_Init(void)
{

  huart1.Instance = USART1;
  huart1.Init.BaudRate = 115200;
  huart1.Init.WordLength = UART_WORDLENGTH_8B;
  huart1.Init.StopBits = UART_STOPBITS_1;
  huart1.Init.Parity = UART_PARITY_NONE;
  huart1.Init.Mode = UART_MODE_TX_RX;
  huart1.Init.HwFlowCtl = UART_HWCONTROL_NONE;
  huart1.Init.OverSampling = UART_OVERSAMPLING_16;
  huart1.Init.OneBitSampling = UART_ONE_BIT_SAMPLE_DISABLE;
  huart1.Init.ClockPrescaler = UART_PRESCALER_DIV1;
  huart1.AdvancedInit.AdvFeatureInit = UART_ADVFEATURE_NO_INIT;
  if (HAL_UART_Init(&huart1) != HAL_OK)
  {
    Error_Handler();
  }
  if (HAL_UARTEx_SetTxFifoThreshold(&huart1, UART_TXFIFO_THRESHOLD_1_8) != HAL_OK)
  {
    Error_Handler();
  }
  if (HAL_UARTEx_SetRxFifoThreshold(&huart1, UART_RXFIFO_THRESHOLD_1_8) != HAL_OK)
  {
    Error_Handler();
  }
  if (HAL_UARTEx_DisableFifoMode(&huart1) != HAL_OK)
  {
    Error_Handler();
  }

}

static void MX_USB_PCD_Init(void)
{

  hpcd_USB_FS.Instance = USB;
  hpcd_USB_FS.Init.dev_endpoints = 8;
  hpcd_USB_FS.Init.speed = PCD_SPEED_FULL;
  hpcd_USB_FS.Init.phy_itface = PCD_PHY_EMBEDDED;
  hpcd_USB_FS.Init.Sof_enable = DISABLE;
  hpcd_USB_FS.Init.low_power_enable = DISABLE;
  hpcd_USB_FS.Init.lpm_enable = DISABLE;
  hpcd_USB_FS.Init.battery_charging_enable = DISABLE;
  if (HAL_PCD_Init(&hpcd_USB_FS) != HAL_OK)
  {
    Error_Handler();
  }

}

static void MX_DMA_Init(void)
{

  /* DMA controller clock enable */
  __HAL_RCC_DMAMUX1_CLK_ENABLE();
  __HAL_RCC_DMA1_CLK_ENABLE();

  /* DMA interrupt init */
  /* DMA1_Channel1_IRQn interrupt configuration */
  HAL_NVIC_SetPriority(DMA1_Channel1_IRQn, 0, 0);
  HAL_NVIC_EnableIRQ(DMA1_Channel1_IRQn);
  /* DMA1_Channel2_IRQn interrupt configuration */
  HAL_NVIC_SetPriority(DMA1_Channel2_IRQn, 0, 0);
  HAL_NVIC_EnableIRQ(DMA1_Channel2_IRQn);

}

static void MX_GPIO_Init(void)
{
  GPIO_InitTypeDef GPIO_InitStruct = {0};

  /* GPIO Ports Clock Enable */
  __HAL_RCC_GPIOC_CLK_ENABLE();
  __HAL_RCC_GPIOF_CLK_ENABLE();
  __HAL_RCC_GPIOG_CLK_ENABLE();
  __HAL_RCC_GPIOA_CLK_ENABLE();
  __HAL_RCC_GPIOB_CLK_ENABLE();
  __HAL_RCC_GPIOD_CLK_ENABLE();

  /*Configure GPIO pin Output Level */
  HAL_GPIO_WritePin(GPIOA, GPIO_PIN_15, GPIO_PIN_SET);

  /*Configure GPIO pin Output Level */
  HAL_GPIO_WritePin(GPIOC, gpio_usb_Pin|gpio_ml_Pin, GPIO_PIN_RESET);

  /*Configure GPIO pin Output Level */
  HAL_GPIO_WritePin(gpio_fl_GPIO_Port, gpio_fl_Pin, GPIO_PIN_SET);

  /*Configure GPIO pin Output Level */
  HAL_GPIO_WritePin(gpio_scope4_GPIO_Port, gpio_scope4_Pin, GPIO_PIN_RESET);

  /*Configure GPIO pin : PG10 */
  GPIO_InitStruct.Pin = GPIO_PIN_10;
  GPIO_InitStruct.Mode = GPIO_MODE_INPUT;
  GPIO_InitStruct.Pull = GPIO_NOPULL;
  HAL_GPIO_Init(GPIOG, &GPIO_InitStruct);

  /*Configure GPIO pins : hall1_Pin hall2_Pin hall3_Pin */
  GPIO_InitStruct.Pin = hall1_Pin|hall2_Pin|hall3_Pin;
  GPIO_InitStruct.Mode = GPIO_MODE_INPUT;
  GPIO_InitStruct.Pull = GPIO_NOPULL;
  HAL_GPIO_Init(GPIOC, &GPIO_InitStruct);

  /*Configure GPIO pin : PA15 */
  GPIO_InitStruct.Pin = GPIO_PIN_15;
  GPIO_InitStruct.Mode = GPIO_MODE_OUTPUT_PP;
  GPIO_InitStruct.Pull = GPIO_NOPULL;
  GPIO_InitStruct.Speed = GPIO_SPEED_FREQ_VERY_HIGH;
  HAL_GPIO_Init(GPIOA, &GPIO_InitStruct);

  /*Configure GPIO pins : gpio_usb_Pin gpio_ml_Pin */
  GPIO_InitStruct.Pin = gpio_usb_Pin|gpio_ml_Pin;
  GPIO_InitStruct.Mode = GPIO_MODE_OUTPUT_PP;
  GPIO_InitStruct.Pull = GPIO_NOPULL;
  GPIO_InitStruct.Speed = GPIO_SPEED_FREQ_LOW;
  HAL_GPIO_Init(GPIOC, &GPIO_InitStruct);

  /*Configure GPIO pin : gpio_fl_Pin */
  GPIO_InitStruct.Pin = gpio_fl_Pin;
  GPIO_InitStruct.Mode = GPIO_MODE_OUTPUT_PP;
  GPIO_InitStruct.Pull = GPIO_NOPULL;
  GPIO_InitStruct.Speed = GPIO_SPEED_FREQ_VERY_HIGH;
  HAL_GPIO_Init(gpio_fl_GPIO_Port, &GPIO_InitStruct);

  /*Configure GPIO pin : gpio_scope4_Pin */
  GPIO_InitStruct.Pin = gpio_scope4_Pin;
  GPIO_InitStruct.Mode = GPIO_MODE_OUTPUT_PP;
  GPIO_InitStruct.Pull = GPIO_NOPULL;
  GPIO_InitStruct.Speed = GPIO_SPEED_FREQ_LOW;
  HAL_GPIO_Init(gpio_scope4_GPIO_Port, &GPIO_InitStruct);

}

void Error_Handler(void)
{
}

/************************ (C) COPYRIGHT STMicroelectronics *****END OF FILE****/
